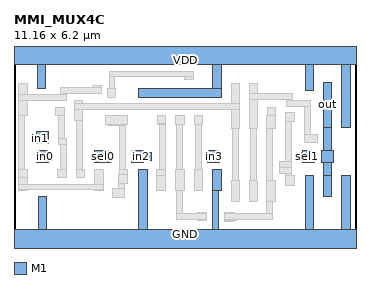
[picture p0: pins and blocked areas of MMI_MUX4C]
MACRO MMI_MUX4C
	CLASS CORE ;
	FOREIGN MMI_MUX4C 0 0 ;
	SIZE 11.16 BY 6.2 ;
	SYMMETRY X Y ;
	SITE CORE1 ;
	PIN out
		DIRECTION output ;
		USE SIGNAL ;
		PORT
			LAYER M1 ;
			RECT 10.095 3.745 10.375 5.215 ;
			LAYER M1 ;
			RECT 10.115 2.98 10.355 3.745 ;
			LAYER M1 ;
			RECT 10.04 2.6 10.42 2.98 ;
			LAYER M1 ;
			RECT 10.115 2.17 10.355 2.6 ;
			LAYER M1 ;
			RECT 10.095 1.47 10.375 2.17 ;
		END
		AntennaDiffArea 1.0164 ;
	END out
	PIN sel0
		DIRECTION input ;
		USE SIGNAL ;
		PORT
			LAYER M1 ;
			RECT 2.64 2.595 3.145 2.985 ;
		END
		AntennaGateArea 0.927 ;
	END sel0
	PIN in1
		DIRECTION input ;
		USE SIGNAL ;
		PORT
			LAYER M1 ;
			RECT 0.74 3.52 1.12 3.6 ;
			LAYER M1 ;
			RECT 0.555 3.24 1.12 3.52 ;
			LAYER M1 ;
			RECT 0.74 3.22 1.12 3.24 ;
		END
		AntennaGateArea 0.3465 ;
	END in1
	PIN GND
		DIRECTION inout ;
		USE GROUND ;
		PORT
			LAYER M1 ;
			RECT 0.79 0.42 1.07 1.495 ;
			LAYER M1 ;
			RECT 4.075 0.42 4.355 2.37 ;
			LAYER M1 ;
			RECT 6.475 1.67 6.755 2.37 ;
			LAYER M1 ;
			RECT 6.48 0.42 6.67 1.67 ;
			LAYER M1 ;
			RECT 9.505 0.42 9.785 2.17 ;
			LAYER M1 ;
			RECT 10.685 0.42 10.965 2.17 ;
			LAYER M1 ;
			RECT 0 -0.42 11.16 0.42 ;
		END
	END GND
	PIN in2
		DIRECTION input ;
		USE SIGNAL ;
		PORT
			LAYER M1 ;
			RECT 3.84 2.93 4.22 2.98 ;
			LAYER M1 ;
			RECT 3.84 2.65 4.48 2.93 ;
			LAYER M1 ;
			RECT 3.84 2.6 4.22 2.65 ;
		END
		AntennaGateArea 0.3465 ;
	END in2
	PIN sel1
		DIRECTION input ;
		USE SIGNAL ;
		PORT
			LAYER M1 ;
			RECT 9.425 2.93 9.8 2.98 ;
			LAYER M1 ;
			RECT 9.305 2.65 9.8 2.93 ;
			LAYER M1 ;
			RECT 9.425 2.6 9.8 2.65 ;
		END
		AntennaGateArea 0.51975 ;
	END sel1
	PIN VDD
		DIRECTION inout ;
		USE POWER ;
		PORT
			LAYER M1 ;
			RECT 0 5.78 11.16 6.62 ;
			LAYER M1 ;
			RECT 0.755 5.025 1.035 5.78 ;
			LAYER M1 ;
			RECT 6.48 5 6.765 5.78 ;
			LAYER M1 ;
			RECT 4.065 4.715 6.765 5 ;
			LAYER M1 ;
			RECT 9.505 4.935 9.785 5.78 ;
			LAYER M1 ;
			RECT 10.685 3.745 10.965 5.78 ;
		END
	END VDD
	PIN in3
		DIRECTION input ;
		USE SIGNAL ;
		PORT
			LAYER M1 ;
			RECT 6.325 2.93 6.7 2.98 ;
			LAYER M1 ;
			RECT 6.325 2.65 6.71 2.93 ;
			LAYER M1 ;
			RECT 6.325 2.6 6.7 2.65 ;
		END
		AntennaGateArea 0.3465 ;
	END in3
	PIN in0
		DIRECTION input ;
		USE SIGNAL ;
		PORT
			LAYER M1 ;
			RECT 0.74 2.93 1.12 2.98 ;
			LAYER M1 ;
			RECT 0.74 2.65 1.265 2.93 ;
			LAYER M1 ;
			RECT 0.74 2.6 1.12 2.65 ;
		END
		AntennaGateArea 0.3465 ;
	END in0
	OBS
		LAYER M1 ;
		RECT 0.16 4.805 0.44 5.175 ;
		LAYER M1 ;
		RECT 5.575 5.575 5.855 5.58 ;
		LAYER M1 ;
		RECT 3.1 5.385 5.855 5.575 ;
		LAYER M1 ;
		RECT 2.565 5.03 2.845 5.11 ;
		LAYER M1 ;
		RECT 1.515 4.835 2.845 5.03 ;
		LAYER M1 ;
		RECT 3.1 5 3.295 5.385 ;
		LAYER M1 ;
		RECT 5.575 5.3 5.855 5.385 ;
		LAYER M1 ;
		RECT 1.515 4.805 1.71 4.835 ;
		LAYER M1 ;
		RECT 2.565 4.83 2.845 4.835 ;
		LAYER M1 ;
		RECT 0.15 4.615 1.71 4.805 ;
		LAYER M1 ;
		RECT 3.045 4.72 3.325 5 ;
		LAYER M1 ;
		RECT 0.15 4.115 0.44 4.615 ;
		LAYER M1 ;
		RECT 1.965 4.515 2.245 4.63 ;
		LAYER M1 ;
		RECT 7.085 4.515 7.365 5.18 ;
		LAYER M1 ;
		RECT 1.36 4.115 1.64 4.395 ;
		LAYER M1 ;
		RECT 0.15 2.37 0.345 4.115 ;
		LAYER M1 ;
		RECT 1.45 3.37 1.64 4.115 ;
		LAYER M1 ;
		RECT 1.965 4.325 7.365 4.515 ;
		LAYER M1 ;
		RECT 1.965 3.96 2.245 4.325 ;
		LAYER M1 ;
		RECT 1.45 3.175 1.705 3.37 ;
		LAYER M1 ;
		RECT 1.51 2.37 1.705 3.175 ;
		LAYER M1 ;
		RECT 2.035 2.37 2.23 3.96 ;
		LAYER M1 ;
		RECT 2.985 3.845 3.71 4.125 ;
		LAYER M1 ;
		RECT 4.67 3.86 4.95 4.12 ;
		LAYER M1 ;
		RECT 2.985 3.84 3.64 3.845 ;
		LAYER M1 ;
		RECT 4.67 3.84 4.955 3.86 ;
		LAYER M1 ;
		RECT 5.275 3.84 5.555 4.12 ;
		LAYER M1 ;
		RECT 5.875 3.84 6.155 4.12 ;
		LAYER M1 ;
		RECT 2.99 3.82 3.64 3.84 ;
		LAYER M1 ;
		RECT 3.075 3.815 3.64 3.82 ;
		LAYER M1 ;
		RECT 3.45 2.37 3.64 3.815 ;
		LAYER M1 ;
		RECT 4.76 2.37 4.955 3.84 ;
		LAYER M1 ;
		RECT 5.31 2.37 5.5 3.84 ;
		LAYER M1 ;
		RECT 5.92 2.37 6.115 3.84 ;
		LAYER M1 ;
		RECT 7.085 3.71 7.365 4.325 ;
		LAYER M1 ;
		RECT 7.675 4.83 7.955 5.18 ;
		LAYER M1 ;
		RECT 7.675 4.64 9.08 4.83 ;
		LAYER M1 ;
		RECT 7.675 3.71 7.955 4.64 ;
		LAYER M1 ;
		RECT 8.885 4.62 9.08 4.64 ;
		LAYER M1 ;
		RECT 8.885 4.425 9.66 4.62 ;
		LAYER M1 ;
		RECT 8.265 4.135 8.545 4.38 ;
		LAYER M1 ;
		RECT 8.25 3.71 8.545 4.135 ;
		LAYER M1 ;
		RECT 8.86 3.94 9.14 4.22 ;
		LAYER M1 ;
		RECT 0.15 2.11 0.44 2.37 ;
		LAYER M1 ;
		RECT 0.16 1.89 0.44 2.11 ;
		LAYER M1 ;
		RECT 1.425 2.09 1.705 2.37 ;
		LAYER M1 ;
		RECT 2.03 2.09 2.31 2.37 ;
		LAYER M1 ;
		RECT 2.625 1.89 2.905 2.37 ;
		LAYER M1 ;
		RECT 3.435 2.2 3.715 2.37 ;
		LAYER M1 ;
		RECT 0.16 1.7 2.905 1.89 ;
		LAYER M1 ;
		RECT 3.425 1.92 3.715 2.2 ;
		LAYER M1 ;
		RECT 3.425 1.745 3.62 1.92 ;
		LAYER M1 ;
		RECT 0.16 1.67 0.44 1.7 ;
		LAYER M1 ;
		RECT 2.625 1.67 2.905 1.7 ;
		LAYER M1 ;
		RECT 3.2 1.465 3.62 1.745 ;
		LAYER M1 ;
		RECT 3.265 1.46 3.62 1.465 ;
		LAYER M1 ;
		RECT 4.665 2.18 4.955 2.37 ;
		LAYER M1 ;
		RECT 4.665 1.67 4.945 2.18 ;
		LAYER M1 ;
		RECT 5.27 1.67 5.55 2.37 ;
		LAYER M1 ;
		RECT 5.885 1.67 6.165 2.37 ;
		LAYER M1 ;
		RECT 7.125 2.015 7.32 3.71 ;
		LAYER M1 ;
		RECT 7.715 2.015 7.91 3.71 ;
		LAYER M1 ;
		RECT 8.25 2.015 8.445 3.71 ;
		LAYER M1 ;
		RECT 8.865 2.62 9.055 3.94 ;
		LAYER M1 ;
		RECT 9.47 3.52 9.66 4.425 ;
		LAYER M1 ;
		RECT 9.47 3.24 9.91 3.52 ;
		LAYER M1 ;
		RECT 8.66 2.43 9.055 2.62 ;
		LAYER M1 ;
		RECT 8.655 2.235 9.055 2.43 ;
		LAYER M1 ;
		RECT 8.865 2.17 9.055 2.235 ;
		LAYER M1 ;
		RECT 5.315 0.925 5.51 1.67 ;
		LAYER M1 ;
		RECT 5.99 0.925 6.27 0.97 ;
		LAYER M1 ;
		RECT 5.315 0.735 6.27 0.925 ;
		LAYER M1 ;
		RECT 5.99 0.69 6.27 0.735 ;
		LAYER M1 ;
		RECT 7.085 1.315 7.365 2.015 ;
		LAYER M1 ;
		RECT 7.675 1.315 7.955 2.015 ;
		LAYER M1 ;
		RECT 8.25 1.315 8.545 2.015 ;
		LAYER M1 ;
		RECT 8.865 1.855 9.145 2.17 ;
		LAYER M1 ;
		RECT 6.875 0.92 7.155 0.965 ;
		LAYER M1 ;
		RECT 8.25 0.92 8.445 1.315 ;
		LAYER M1 ;
		RECT 6.875 0.725 8.445 0.92 ;
		LAYER M1 ;
		RECT 6.875 0.715 7.255 0.725 ;
		LAYER M1 ;
		RECT 6.875 0.685 7.155 0.715 ;
	END
END MMI_MUX4C
